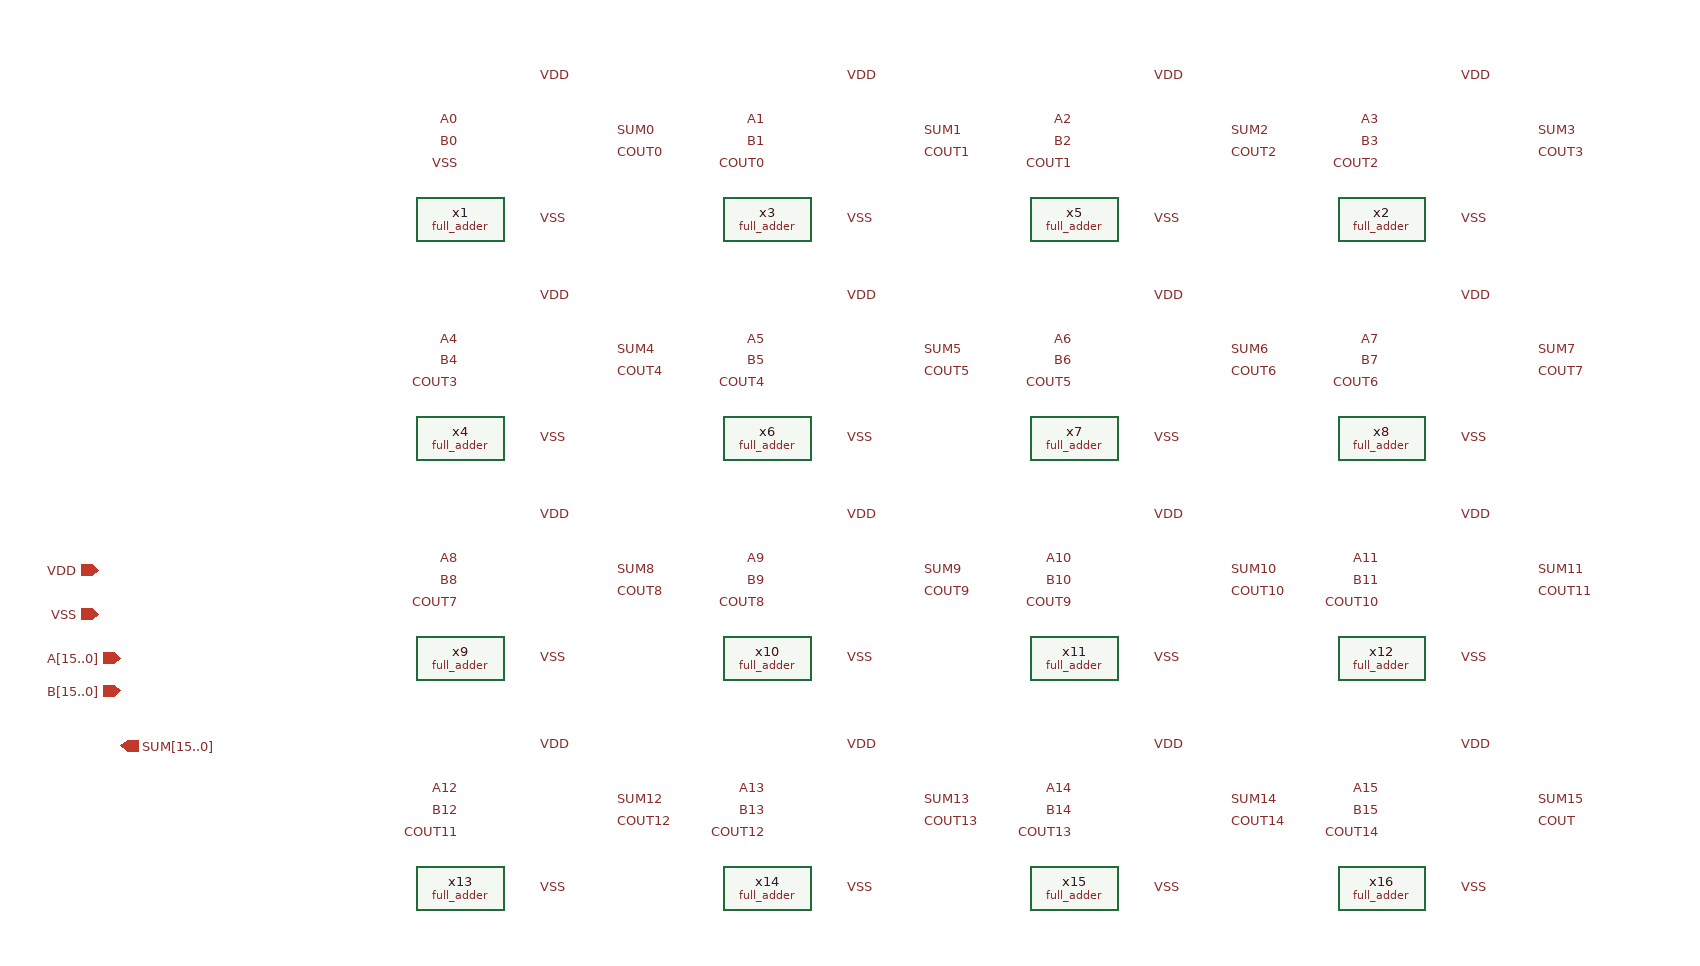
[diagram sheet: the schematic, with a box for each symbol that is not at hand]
v {xschem version=3.4.7 file_version=1.2}
G {}
K {}
V {}
S {}
E {}
C {engn1600-team1/CAD6/full_adder.sym} 380 -690 0 0 {name=x1 kSUMb=1 kTS=1}
C {lab_pin.sym} 450 -820 0 1 {name=p1 lab=VDD}
C {lab_pin.sym} 450 -690 0 1 {name=p2 lab=VSS}
C {lab_pin.sym} 380 -780 0 0 {name=p3 lab=A0}
C {lab_pin.sym} 380 -760 0 0 {name=p4 lab=B0}
C {lab_pin.sym} 380 -740 0 0 {name=p5 lab=VSS}
C {lab_pin.sym} 520 -770 0 1 {name=p6 lab=SUM0}
C {ipin.sym} 70 -290 0 0 {name=p8 lab=A[15..0]}
C {ipin.sym} 70 -260 0 0 {name=p9 lab=B[15..0]}
C {iopin.sym} 50 -370 0 0 {name=p10 lab=VDD}
C {iopin.sym} 50 -330 0 0 {name=p11 lab=VSS}
C {opin.sym} 70 -210 0 0 {name=p15 lab=SUM[15..0]}
C {engn1600-team1/CAD6/full_adder.sym} 660 -690 0 0 {name=x3 kSUMb=1 kTS=1}
C {lab_pin.sym} 730 -820 0 1 {name=p17 lab=VDD}
C {lab_pin.sym} 730 -690 0 1 {name=p18 lab=VSS}
C {lab_pin.sym} 660 -780 0 0 {name=p19 lab=A1}
C {lab_pin.sym} 660 -760 0 0 {name=p20 lab=B1}
C {lab_pin.sym} 800 -770 0 1 {name=p21 lab=SUM1}
C {engn1600-team1/CAD6/full_adder.sym} 940 -690 0 0 {name=x5 kSUMb=1 kTS=1}
C {lab_pin.sym} 1010 -820 0 1 {name=p27 lab=VDD}
C {lab_pin.sym} 1010 -690 0 1 {name=p28 lab=VSS}
C {lab_pin.sym} 940 -780 0 0 {name=p29 lab=A2}
C {lab_pin.sym} 940 -760 0 0 {name=p30 lab=B2}
C {lab_pin.sym} 1080 -770 0 1 {name=p31 lab=SUM2}
C {engn1600-team1/CAD6/full_adder.sym} 1220 -690 0 0 {name=x2 kSUMb=1 kTS=1}
C {lab_pin.sym} 1290 -820 0 1 {name=p7 lab=VDD}
C {lab_pin.sym} 1290 -690 0 1 {name=p12 lab=VSS}
C {lab_pin.sym} 1220 -780 0 0 {name=p13 lab=A3}
C {lab_pin.sym} 1220 -760 0 0 {name=p14 lab=B3}
C {lab_pin.sym} 1360 -770 0 1 {name=p16 lab=SUM3}
C {lab_pin.sym} 520 -750 0 1 {name=p22 lab=COUT0}
C {lab_pin.sym} 660 -740 0 0 {name=p23 lab=COUT0}
C {lab_pin.sym} 800 -750 0 1 {name=p24 lab=COUT1}
C {lab_pin.sym} 940 -740 0 0 {name=p25 lab=COUT1
}
C {lab_pin.sym} 1080 -750 0 1 {name=p26 lab=COUT2}
C {lab_pin.sym} 1220 -740 0 0 {name=p32 lab=COUT2}
C {lab_pin.sym} 1360 -750 0 1 {name=p33 lab=COUT3}
C {engn1600-team1/CAD6/full_adder.sym} 380 -490 0 0 {name=x4 kSUMb=1 kTS=1}
C {lab_pin.sym} 450 -620 0 1 {name=p34 lab=VDD}
C {lab_pin.sym} 450 -490 0 1 {name=p35 lab=VSS}
C {lab_pin.sym} 380 -580 0 0 {name=p36 lab=A4}
C {lab_pin.sym} 380 -560 0 0 {name=p37 lab=B4}
C {lab_pin.sym} 380 -540 0 0 {name=p38 lab=COUT3}
C {lab_pin.sym} 520 -570 0 1 {name=p39 lab=SUM4}
C {engn1600-team1/CAD6/full_adder.sym} 660 -490 0 0 {name=x6 kSUMb=1 kTS=1}
C {lab_pin.sym} 730 -620 0 1 {name=p40 lab=VDD}
C {lab_pin.sym} 730 -490 0 1 {name=p41 lab=VSS}
C {lab_pin.sym} 660 -580 0 0 {name=p42 lab=A5}
C {lab_pin.sym} 660 -560 0 0 {name=p43 lab=B5}
C {lab_pin.sym} 800 -570 0 1 {name=p44 lab=SUM5}
C {engn1600-team1/CAD6/full_adder.sym} 940 -490 0 0 {name=x7 kSUMb=1 kTS=1}
C {lab_pin.sym} 1010 -620 0 1 {name=p45 lab=VDD}
C {lab_pin.sym} 1010 -490 0 1 {name=p46 lab=VSS}
C {lab_pin.sym} 940 -580 0 0 {name=p47 lab=A6}
C {lab_pin.sym} 940 -560 0 0 {name=p48 lab=B6}
C {lab_pin.sym} 1080 -570 0 1 {name=p49 lab=SUM6}
C {engn1600-team1/CAD6/full_adder.sym} 1220 -490 0 0 {name=x8 kSUMb=1 kTS=1}
C {lab_pin.sym} 1290 -620 0 1 {name=p50 lab=VDD}
C {lab_pin.sym} 1290 -490 0 1 {name=p51 lab=VSS}
C {lab_pin.sym} 1220 -580 0 0 {name=p52 lab=A7}
C {lab_pin.sym} 1220 -560 0 0 {name=p53 lab=B7}
C {lab_pin.sym} 1360 -570 0 1 {name=p54 lab=SUM7}
C {lab_pin.sym} 520 -550 0 1 {name=p55 lab=COUT4}
C {lab_pin.sym} 660 -540 0 0 {name=p56 lab=COUT4}
C {lab_pin.sym} 800 -550 0 1 {name=p57 lab=COUT5}
C {lab_pin.sym} 940 -540 0 0 {name=p58 lab=COUT5
}
C {lab_pin.sym} 1080 -550 0 1 {name=p59 lab=COUT6}
C {lab_pin.sym} 1220 -540 0 0 {name=p60 lab=COUT6}
C {lab_pin.sym} 1360 -550 0 1 {name=p61 lab=COUT7}
C {engn1600-team1/CAD6/full_adder.sym} 380 -290 0 0 {name=x9 kSUMb=1 kTS=1}
C {lab_pin.sym} 450 -420 0 1 {name=p62 lab=VDD}
C {lab_pin.sym} 450 -290 0 1 {name=p63 lab=VSS}
C {lab_pin.sym} 380 -380 0 0 {name=p64 lab=A8}
C {lab_pin.sym} 380 -360 0 0 {name=p65 lab=B8}
C {lab_pin.sym} 380 -340 0 0 {name=p66 lab=COUT7}
C {lab_pin.sym} 520 -370 0 1 {name=p67 lab=SUM8}
C {engn1600-team1/CAD6/full_adder.sym} 660 -290 0 0 {name=x10 kSUMb=1 kTS=1}
C {lab_pin.sym} 730 -420 0 1 {name=p68 lab=VDD}
C {lab_pin.sym} 730 -290 0 1 {name=p69 lab=VSS}
C {lab_pin.sym} 660 -380 0 0 {name=p70 lab=A9}
C {lab_pin.sym} 660 -360 0 0 {name=p71 lab=B9}
C {lab_pin.sym} 800 -370 0 1 {name=p72 lab=SUM9}
C {engn1600-team1/CAD6/full_adder.sym} 940 -290 0 0 {name=x11 kSUMb=1 kTS=1}
C {lab_pin.sym} 1010 -420 0 1 {name=p73 lab=VDD}
C {lab_pin.sym} 1010 -290 0 1 {name=p74 lab=VSS}
C {lab_pin.sym} 940 -380 0 0 {name=p75 lab=A10}
C {lab_pin.sym} 940 -360 0 0 {name=p76 lab=B10}
C {lab_pin.sym} 1080 -370 0 1 {name=p77 lab=SUM10}
C {engn1600-team1/CAD6/full_adder.sym} 1220 -290 0 0 {name=x12 kSUMb=1 kTS=1}
C {lab_pin.sym} 1290 -420 0 1 {name=p78 lab=VDD}
C {lab_pin.sym} 1290 -290 0 1 {name=p79 lab=VSS}
C {lab_pin.sym} 1220 -380 0 0 {name=p80 lab=A11}
C {lab_pin.sym} 1220 -360 0 0 {name=p81 lab=B11}
C {lab_pin.sym} 1360 -370 0 1 {name=p82 lab=SUM11}
C {lab_pin.sym} 520 -350 0 1 {name=p83 lab=COUT8}
C {lab_pin.sym} 660 -340 0 0 {name=p84 lab=COUT8}
C {lab_pin.sym} 800 -350 0 1 {name=p85 lab=COUT9}
C {lab_pin.sym} 940 -340 0 0 {name=p86 lab=COUT9
}
C {lab_pin.sym} 1080 -350 0 1 {name=p87 lab=COUT10}
C {lab_pin.sym} 1220 -340 0 0 {name=p88 lab=COUT10}
C {lab_pin.sym} 1360 -350 0 1 {name=p89 lab=COUT11}
C {engn1600-team1/CAD6/full_adder.sym} 380 -80 0 0 {name=x13 kSUMb=1 kTS=1}
C {lab_pin.sym} 450 -210 0 1 {name=p90 lab=VDD}
C {lab_pin.sym} 450 -80 0 1 {name=p91 lab=VSS}
C {lab_pin.sym} 380 -170 0 0 {name=p92 lab=A12}
C {lab_pin.sym} 380 -150 0 0 {name=p93 lab=B12}
C {lab_pin.sym} 380 -130 0 0 {name=p94 lab=COUT11}
C {lab_pin.sym} 520 -160 0 1 {name=p95 lab=SUM12}
C {engn1600-team1/CAD6/full_adder.sym} 660 -80 0 0 {name=x14 kSUMb=1 kTS=1}
C {lab_pin.sym} 730 -210 0 1 {name=p96 lab=VDD}
C {lab_pin.sym} 730 -80 0 1 {name=p97 lab=VSS}
C {lab_pin.sym} 660 -170 0 0 {name=p98 lab=A13}
C {lab_pin.sym} 660 -150 0 0 {name=p99 lab=B13}
C {lab_pin.sym} 800 -160 0 1 {name=p100 lab=SUM13}
C {engn1600-team1/CAD6/full_adder.sym} 940 -80 0 0 {name=x15 kSUMb=1 kTS=1}
C {lab_pin.sym} 1010 -210 0 1 {name=p101 lab=VDD}
C {lab_pin.sym} 1010 -80 0 1 {name=p102 lab=VSS}
C {lab_pin.sym} 940 -170 0 0 {name=p103 lab=A14}
C {lab_pin.sym} 940 -150 0 0 {name=p104 lab=B14}
C {lab_pin.sym} 1080 -160 0 1 {name=p105 lab=SUM14}
C {engn1600-team1/CAD6/full_adder.sym} 1220 -80 0 0 {name=x16 kSUMb=1 kTS=1}
C {lab_pin.sym} 1290 -210 0 1 {name=p106 lab=VDD}
C {lab_pin.sym} 1290 -80 0 1 {name=p107 lab=VSS}
C {lab_pin.sym} 1220 -170 0 0 {name=p108 lab=A15}
C {lab_pin.sym} 1220 -150 0 0 {name=p109 lab=B15}
C {lab_pin.sym} 1360 -160 0 1 {name=p110 lab=SUM15}
C {lab_pin.sym} 520 -140 0 1 {name=p111 lab=COUT12}
C {lab_pin.sym} 660 -130 0 0 {name=p112 lab=COUT12}
C {lab_pin.sym} 800 -140 0 1 {name=p113 lab=COUT13}
C {lab_pin.sym} 940 -130 0 0 {name=p114 lab=COUT13
}
C {lab_pin.sym} 1080 -140 0 1 {name=p115 lab=COUT14}
C {lab_pin.sym} 1220 -130 0 0 {name=p116 lab=COUT14}
C {lab_pin.sym} 1360 -140 0 1 {name=p117 lab=COUT}
